VERSION 5.7 ;
  NOWIREEXTENSIONATPIN ON ;
  DIVIDERCHAR "/" ;
  BUSBITCHARS "[]" ;
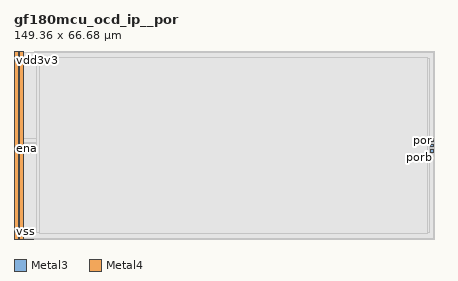
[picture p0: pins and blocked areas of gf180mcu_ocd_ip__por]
MACRO gf180mcu_ocd_ip__por
  CLASS BLOCK ;
  FOREIGN gf180mcu_ocd_ip__por ;
  ORIGIN 0.000 0.000 ;
  SIZE 149.360 BY 66.680 ;
  PIN ena
    DIRECTION INPUT ;
    USE SIGNAL ;
    ANTENNAGATEAREA 3.360000 ;
    ANTENNADIFFAREA 0.202500 ;
    PORT
      LAYER Metal3 ;
        RECT 0.000 31.820 1.000 32.820 ;
    END
  END ena
  PIN por_unbuf
    DIRECTION OUTPUT ;
    USE SIGNAL ;
    ANTENNAGATEAREA 10.371200 ;
    ANTENNADIFFAREA 0.712200 ;
    PORT
      LAYER Metal3 ;
        RECT 148.125 32.750 149.125 33.750 ;
    END
  END por_unbuf
  PIN porb
    DIRECTION OUTPUT ;
    USE SIGNAL ;
    ANTENNADIFFAREA 7.461300 ;
    PORT
      LAYER Metal3 ;
        RECT 148.115 30.830 149.115 31.830 ;
    END
  END porb
  PIN por
    DIRECTION OUTPUT ;
    USE SIGNAL ;
    ANTENNADIFFAREA 7.461300 ;
    PORT
      LAYER Metal3 ;
        RECT 148.120 34.600 149.120 35.600 ;
    END
  END por
  PIN vss
    DIRECTION INOUT ;
    USE GROUND ;
    PORT
      LAYER Metal4 ;
        RECT 0.000 0.000 1.500 66.680 ;
    END
  END vss
  PIN vdd3v3
    DIRECTION INOUT ;
    USE POWER ;
    PORT
      LAYER Metal4 ;
        RECT 1.780 0.000 3.280 66.680 ;
    END
  END vdd3v3
  OBS
      LAYER Nwell ;
        RECT 7.350 0.000 149.360 66.680 ;
      LAYER Metal1 ;
        RECT 0.000 0.180 149.180 66.495 ;
      LAYER Metal2 ;
        RECT 0.000 0.180 149.180 66.490 ;
      LAYER Metal3 ;
        RECT 0.000 35.900 149.240 66.500 ;
        RECT 0.000 34.300 147.820 35.900 ;
        RECT 0.000 34.050 149.240 34.300 ;
        RECT 0.000 33.120 147.825 34.050 ;
        RECT 1.300 32.450 147.825 33.120 ;
        RECT 1.300 32.130 149.240 32.450 ;
        RECT 1.300 31.520 147.815 32.130 ;
        RECT 0.000 30.530 147.815 31.520 ;
        RECT 0.000 0.185 149.240 30.530 ;
      LAYER Metal4 ;
        RECT 7.845 2.335 147.880 64.350 ;
      LAYER Metal5 ;
        RECT 8.940 2.125 146.880 64.575 ;
  END
END gf180mcu_ocd_ip__por
END LIBRARY

